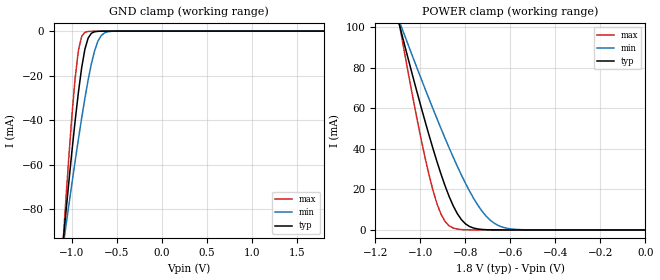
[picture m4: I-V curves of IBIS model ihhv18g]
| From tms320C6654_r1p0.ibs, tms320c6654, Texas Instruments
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|   Model Cell ihhv18g
|ihhv18g (15Jun10 rev 1.0)
[Model]   ihhv18g
Model_type   Input
Polarity   Non-Inverting
Vinl =  0.63
Vinh =  1.17
C_comp   0.720p   0.675p   0.780p
[Model Spec]
Vinl   0.63   0.567   0.693
Vinh   1.17   1.053   1.287
[Temperature Range]   25   125   -40
[Voltage Range]   1.8   1.62   1.98
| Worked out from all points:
|   GND clamp passes 1 mA (typ) near -0.78 V on its own axis
|   POWER clamp passes 1 mA (typ) near -0.77 V on its own axis
[POWER_clamp]
|   voltage   I(typ)   I(min)   I(max)
-1.8V     427.4mA    323.1mA    578.5mA
-1.091V   99.96mA    102mA      99.75mA
-1.073V   92.13mA    96.64mA    88.56mA
-1V       61.75mA    75.45mA    46.3mA
-945.5mV  40.53mA    60.06mA    19.94mA
-909.1mV  27.67mA    50.12mA    7.835mA
-890.9mV  21.84mA    45.28mA    4.198mA
-854.5mV  11.92mA    35.94mA    955.8uA
-800mV    3.016mA    23.04mA    99.12uA
-727.3mV  255.8uA    9.408mA    23.91uA
-636.4mV  15.65uA    1.427mA    11.93uA
0V        9.084nA    6.352nA    18.51nA
[GND_clamp]
|   voltage   I(typ)   I(min)   I(max)
-1.8V     -418.5mA   -315.4mA   -568mA
-1.109V   -99.79mA   -100.3mA   -101.8mA
-1.073V   -84.23mA   -89.57mA   -79.54mA
-1V       -54.36mA   -68.62mA   -38.49mA
-963.6mV  -40.44mA   -58.46mA   -21.38mA
-927.3mV  -27.62mA   -48.59mA   -8.794mA
-854.5mV  -8.093mA   -30.11mA   -555.2uA
-818.2mV  -3.065mA   -21.83mA   -158.2uA
-745.5mV  -287.2uA   -8.633mA   -61.8uA
-672.7mV  -47.68uA   -1.975mA   -44.61uA
-600mV    -23.52uA   -304.6uA   -31.26uA
1.8V      9.084nA    10.54nA    18.45nA
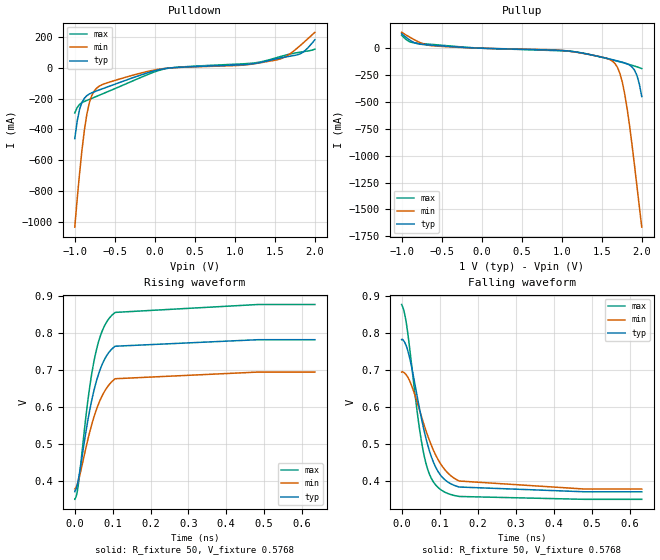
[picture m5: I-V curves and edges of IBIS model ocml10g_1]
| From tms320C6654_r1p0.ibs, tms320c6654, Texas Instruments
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|   Model Cell OCML10G_1
|OCML10G_1
[Model]   ocml10g_1
Model_type   Output
Polarity   Non-Inverting
Cref =  1PF
Rref =  1M
Vref =  0V
Vmeas =  0.5768V
C_comp   1p   1p   1p
| Input capacitance of this buffer has no significance since this is output only
| buffer
[Temperature Range]   25   125   -40
[Voltage Range]   1   0.9   1.1
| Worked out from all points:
|   slope of the pulldown table from 0 to 0.15 V, typ, clamps not added: 9.66 ohm
|   slope of the pullup table from 0 to 0.15 V, typ, clamps not added: 47.7 ohm
|   rising waveform, R_fixture 50, V_fixture 0.5768: 20-80 % time 49.1ps typ, 53.7ps min, 44.6ps max; typ from 0.372 V to 0.781 V
|   falling waveform, R_fixture 50, V_fixture 0.5768: 20-80 % time 54.8ps typ, 70.4ps min, 42.4ps max; typ from 0.782 V to 0.371 V
[Pulldown]
|   voltage   I(typ)   I(min)   I(max)
-1V       -459.5mA   -1.033A    -293.1mA
-969.7mV  -345.3mA   -849.8mA   -257.9mA
-939.4mV  -268.5mA   -680.3mA   -237.8mA
-878.8mV  -197mA     -400.4mA   -218.5mA
-848.5mV  -181mA     -299.6mA   -211.9mA
-787.9mV  -162.9mA   -180.5mA   -198.9mA
-727.3mV  -150.6mA   -132.7mA   -185.8mA
121.2mV   -6.284mA   -5.231mA   -8.248mA
1.212V    24.19mA    22.83mA    28.91mA
1.545V    60.65mA    53.28mA    68.55mA
1.818V    90.11mA    143.8mA    100.5mA
2V        180.8mA    228.9mA    120.2mA
[Pullup]
|   voltage   I(typ)   I(min)   I(max)
-1V       135.5mA    148.5mA    121.9mA
-878.8mV  67.11mA    94.67mA    55.54mA
-636.4mV  29.12mA    25.15mA    37.1mA
1V        -20.19mA   -20.07mA   -23.6mA
1.636V    -106.8mA   -121.2mA   -108.9mA
1.697V    -118.1mA   -178.5mA   -120.6mA
1.727V    -123.9mA   -234.2mA   -126.5mA
1.788V    -136.8mA   -428.2mA   -138.8mA
1.848V    -156.7mA   -724.4mA   -151.7mA
1.909V    -202.8mA   -1.087A    -165.3mA
1.97V     -331.7mA   -1.472A    -180.1mA
2V        -449.3mA   -1.665A    -188.9mA
[Ramp]
| variable   typ   min   max
dV/dt_f   0.248106/55.026052p   0.190656/70.675323p   0.317478/42.516298p
dV/dt_r   0.246402/49.335231p   0.19083/54.65788p   0.315288/44.687748p
R_load = 50
[Rising Waveform]
R_fixture = 50
V_fixture = 0.5768
V_fixture_min = 0.5368
V_fixture_max = 0.6138
|   time   V(typ)   V(min)   V(max)
0s        371.9mV    379.2mV    351.2mV
4.681ps   382.7mV    386.4mV    362.9mV
8.681ps   400.2mV    398.4mV    385.5mV
34.68ps   564.8mV    512.9mV    618.4mV
42.68ps   608mV      545mV      676.2mV
52.68ps   652.9mV    579.7mV    733.4mV
62.68ps   688.4mV    608.1mV    775.7mV
74.68ps   720.2mV    634.9mV    810.5mV
104.7ps   762.4mV    674.7mV    853.5mV
634.1ps   781.5mV    694.3mV    876.4mV
[Falling Waveform]
R_fixture = 50
V_fixture = 0.5768
V_fixture_min = 0.5368
V_fixture_max = 0.6138
0s        781.7mV    694.4mV    876.7mV
9.264ps   771.9mV    690.1mV    844.3mV
19.26ps   740mV      674.3mV    773.8mV
41.26ps   626.1mV    610.7mV    582.9mV
57.26ps   544.1mV    557mV      477.7mV
75.26ps   474.2mV    503.7mV    413.2mV
99.26ps   420.1mV    451.7mV    379.6mV
123.3ps   396.2mV    419.9mV    365.8mV
151.3ps   384mV      400.2mV    358.5mV
630.7ps   371.1mV    378.6mV    350.8mV
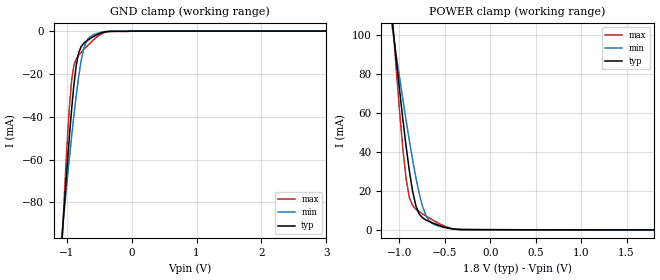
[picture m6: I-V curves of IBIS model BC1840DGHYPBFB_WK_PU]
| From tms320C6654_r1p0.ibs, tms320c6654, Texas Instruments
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|   Model Cell BC1840DGHYPBFB_WK_PU
|BC1840DGHYPBFB_WK_PU
[Model]   BC1840DGHYPBFB_WK_PU
Model_type   Input
Polarity   Non-Inverting
Vinl =  0.63
Vinh =  1.17
C_comp   1.10911p   1.03952p   1.18892p
[Model Spec]
Vinl   0.63   0.5985   0.6615
Vinh   1.17   1.1115   1.2285
D_overshoot_high 2.34 2.34 2.34
D_overshoot_low -0.3 -0.3 -0.3
D_overshoot_time 1.00E-09 1.00E-09 1.00E-09
S_overshoot_high 1.98 1.98 1.98
S_overshoot_low 0 0 0
[Temperature Range]   25   105   -40
[Voltage Range]   1.8   1.71   1.89
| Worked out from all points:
|   GND clamp passes 1 mA (typ) near -0.48 V on its own axis
|   POWER clamp passes 1 mA (typ) near -0.48 V on its own axis
[POWER_clamp]
|   voltage   I(typ)   I(min)   I(max)
-1.8V     457.5mA    350.7mA    618.6mA
-1.073V   104mA      101.6mA    105.6mA
-963.6mV  57.12mA    67.15mA    42mA
-927.3mV  42.94mA    56.22mA    26.36mA
-890.9mV  30.15mA    45.7mA     16.54mA
-854.5mV  19.56mA    35.74mA    12.31mA
-818.2mV  12.08mA    26.56mA    10.46mA
-745.5mV  6.059mA    11.95mA    8.106mA
-709.1mV  4.989mA    7.331mA    7.036mA
-600mV    2.84mA     2.301mA    4.047mA
-345.5mV  117.4uA    127.3uA    127.6uA
1.8V      -99.58uA   -64.22uA   -149.9uA
[GND_clamp]
|   voltage   I(typ)   I(min)   I(max)
-1.8V     -448.8mA   -342.6mA   -610mA
-1.073V   -96.83mA   -94.35mA   -98.27mA
-1.036V   -80.83mA   -82.8mA    -75.88mA
-963.6mV  -50.64mA   -60.42mA   -36.89mA
-927.3mV  -37.05mA   -49.74mA   -23.34mA
-890.9mV  -25.19mA   -39.54mA   -15.97mA
-818.2mV  -10.27mA   -21.49mA   -11.34mA
-745.5mV  -5.941mA   -8.933mA   -8.832mA
-672.7mV  -4.189mA   -3.602mA   -6.523mA
-600mV    -2.783mA   -1.908mA   -4.398mA
-309.1mV  -119.3uA   -82.54uA   -180.5uA
3.6V      0A         0A         0A
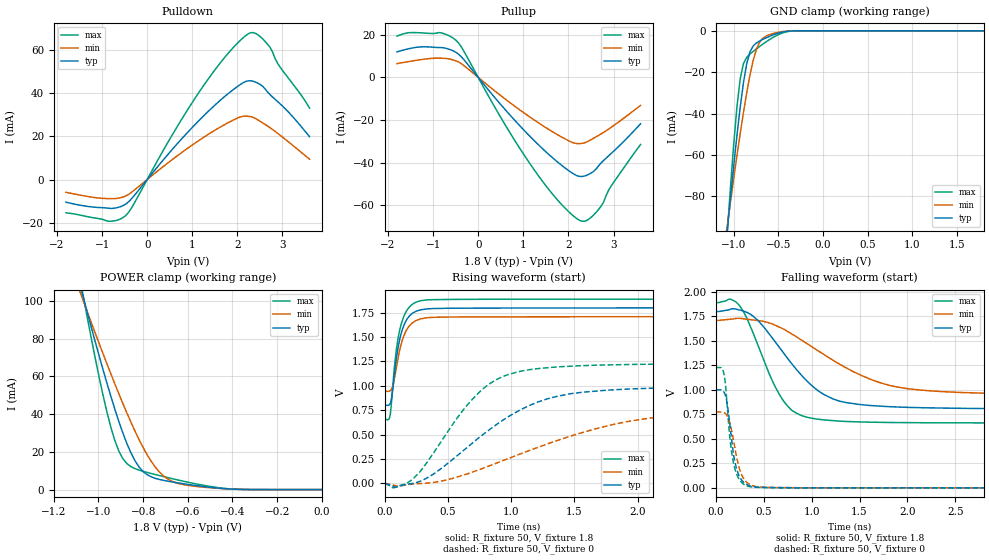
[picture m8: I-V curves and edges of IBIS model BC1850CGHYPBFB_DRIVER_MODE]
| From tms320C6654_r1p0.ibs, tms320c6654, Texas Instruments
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|   Model Cell BC1850CGHYPBFB_DRIVER_MODE
|BC1850CGHYPBFB_DRIVER_MODE
[Model]   BC1850CGHYPBFB_DRIVER_MODE
Model_type   I/O
Polarity   Non-Inverting
Enable   Active-Low
Vinl =  0.63
Vinh =  1.17
Cref = 5.0000pF
Rref =  100.0000M
Vref =  0V
Vmeas =  0.9
C_comp   1.03817p   0.972267p   1.11381p
[Model Spec]
Vinl   0.63   0.5985   0.6615
Vinh   1.17   1.1115   1.2285
D_overshoot_high 2.34 2.34 2.34
D_overshoot_low -0.3 -0.3 -0.3
D_overshoot_time 1.00E-09 1.00E-09 1.00E-09
S_overshoot_high 1.98 1.98 1.98
S_overshoot_low 0 0 0
[Temperature Range]   25   105   -40
[Voltage Range]   1.8   1.71   1.89
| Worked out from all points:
|   slope of the pulldown table from 0 to 0.27 V, typ, clamps not added: 38.9 ohm
|   slope of the pullup table from 0 to 0.27 V, typ, clamps not added: 38.5 ohm
|   GND clamp passes 1 mA (typ) near -0.49 V on its own axis
|   POWER clamp passes 1 mA (typ) near -0.48 V on its own axis
|   rising waveform, R_fixture 50, V_fixture 1.8: 20-80 % time 78.8ps typ, 86.2ps min, 74.9ps max; typ from 0.807 V to 1.8 V
|   rising waveform, R_fixture 50, V_fixture 0: 20-80 % time 652ps typ, 1.09ns min, 440ps max; typ from 0 V to 0.999 V
|   falling waveform, R_fixture 50, V_fixture 1.8: 20-80 % time 517ps typ, 822ps min, 331ps max; typ from 1.8 V to 0.806 V
|   falling waveform, R_fixture 50, V_fixture 0: 20-80 % time 87.6ps typ, 103ps min, 78.9ps max; typ from 1 V to 0 V
[POWER_clamp]
|   voltage   I(typ)   I(min)   I(max)
-1.8V     457.5mA    350.7mA    618.6mA
-1.073V   104mA      101.5mA    105.5mA
-1.055V   95.87mA    95.68mA    93.98mA
-1V       72.13mA    78.37mA    61.22mA
-945.5mV  49.82mA    61.61mA    33.45mA
-909.1mV  36.25mA    50.87mA    20.48mA
-872.7mV  24.44mA    40.61mA    13.8mA
-800mV    9.556mA    22.31mA    9.682mA
-727.3mV  5.377mA    9.342mA    7.443mA
-654.5mV  3.753mA    3.696mA    5.378mA
-400mV    266.8uA    273.8uA    300.1uA
0V        10.43nA    15.61nA    15.97nA
[Pulldown]
|   voltage   I(typ)   I(min)   I(max)
-1.8V     -10.49mA   -5.94mA    -15.44mA
-872.7mV  -13.28mA   -8.846mA   -19.37mA
-490.9mV  -11.6mA    -7.765mA   -16.98mA
-327.3mV  -8.437mA   -5.603mA   -12.48mA
490.9mV   12.41mA    8.221mA    18.41mA
1.2V      28.49mA    18.87mA    42.06mA
1.855V    40.86mA    27.04mA    60mA
2.291V    45.84mA    29.18mA    68.13mA
2.455V    44.73mA    27.66mA    67.19mA
2.673V    40.54mA    24.78mA    62.7mA
2.891V    36.19mA    21.48mA    53.96mA
3.6V      19.87mA    9.45mA     33.15mA
[Pullup]
|   voltage   I(typ)   I(min)   I(max)
-1.8V     11.99mA    6.48mA     19.36mA
-1.309V   14.25mA    8.213mA    20.96mA
-872.7mV  13.99mA    9.018mA    21.04mA
-490.9mV  11.72mA    7.718mA    17.37mA
600mV     -15.19mA   -10.2mA    -22.37mA
1.145V    -27.66mA   -18.63mA   -40.48mA
1.745V    -39.51mA   -26.77mA   -57.27mA
2.236V    -46.48mA   -31.14mA   -67.04mA
2.4V      -46.04mA   -30.43mA   -67.27mA
2.673V    -41.48mA   -27.21mA   -61.93mA
2.945V    -35.82mA   -23.52mA   -51.11mA
3.6V      -21.79mA   -13.16mA   -31.53mA
[GND_clamp]
|   voltage   I(typ)   I(min)   I(max)
-1.8V     -448.8mA   -342.6mA   -610mA
-1.073V   -96.78mA   -94.34mA   -98.17mA
-1.036V   -80.78mA   -82.78mA   -75.78mA
-963.6mV  -50.58mA   -60.4mA    -36.78mA
-927.3mV  -36.98mA   -49.71mA   -23.23mA
-890.9mV  -25.12mA   -39.52mA   -15.86mA
-854.5mV  -15.96mA   -30.01mA   -12.84mA
-818.2mV  -10.19mA   -21.46mA   -11.22mA
-745.5mV  -5.863mA   -8.89mA    -8.713mA
-636.4mV  -3.378mA   -2.511mA   -5.306mA
-345.5mV  -56.35uA   -45.43uA   -97.06uA
1.8V      10.43nA    77.52nA    15.84nA
[Ramp]
| variable   typ   min   max
dV/dt_f   0.614472/0.52822932n   0.47157/0.83950154n   0.758814/0.33831193n
dV/dt_r  0.6235026/0.66882898n  0.4837782/1.1184342n   0.766041/0.45055837n
R_load = 50
[Rising Waveform]
R_fixture = 50
V_fixture = 1.8
V_fixture_min = 1.71
V_fixture_max = 1.89
|   time   V(typ)   V(min)   V(max)
0s        806.9mV    947mV      662.1mV
41.85ps   815.1mV    949.1mV    694.7mV
55.46ps   887.2mV    970.4mV    878.2mV
73.64ps   1.092V     1.057V     1.163V
90.83ps   1.275V     1.186V     1.366V
109.4ps   1.424V     1.319V     1.52V
134ps     1.559V     1.451V     1.652V
191.3ps   1.712V     1.611V     1.804V
289.3ps   1.781V     1.689V     1.875V
4.965ns   1.8V       1.71V      1.89V
[Rising Waveform]
R_fixture = 50
V_fixture = 0
V_fixture_min = 0
V_fixture_max = 0
|   time   V(typ)   V(min)   V(max)
0s        0V         0V         0V
71.55ps   -35.14mV   -20.62mV   -46.99mV
207.6ps   -5.47mV    -9.875mV   28.97mV
388.1ps   96.57mV    8.689mV    316mV
759.8ps   482.6mV    145.3mV    949.5mV
919.3ps   634.8mV    224.2mV    1.087V
1.107ns   775.5mV    317.8mV    1.158V
1.464ns   917.9mV    481.4mV    1.201V
2.348ns   982.8mV    704.6mV    1.225V
4.965ns   999.4mV    775mV      1.229V
[Falling Waveform]
R_fixture = 50
V_fixture = 1.8
V_fixture_min = 1.71
V_fixture_max = 1.89
|   time   V(typ)   V(min)   V(max)
0s        1.8V       1.709V     1.89V
145.3ps   1.82V      1.72V      1.927V
242.5ps   1.817V     1.732V     1.867V
439.3ps   1.71V      1.71V      1.455V
664.7ps   1.432V     1.641V     950.6mV
797.2ps   1.262V     1.57V      789.1mV
953.5ps   1.089V     1.471V     720.7mV
1.291ns   885.1mV    1.263V     681.1mV
1.999ns   821.8mV    1.013V     665.6mV
4.965ns   805.9mV    946.6mV    662.5mV
[Falling Waveform]
R_fixture = 50
V_fixture = 0
V_fixture_min = 0
V_fixture_max = 0
|   time   V(typ)   V(min)   V(max)
0s        999.8mV    775.2mV    1.228V
57.9ps    999.4mV    775.8mV    1.226V
87.43ps   973.4mV    768.3mV    1.153V
118.6ps   862.1mV    735.5mV    840.1mV
151.1ps   602.8mV    646.4mV    470.1mV
196.9ps   277.6mV    416.4mV    201.2mV
258.9ps   94.56mV    158.2mV    66.95mV
334.4ps   28.2mV     48.13mV    16.1mV
592.9ps   3.231mV    3.261mV    2.282mV
4.965ns   0V         0V         0V
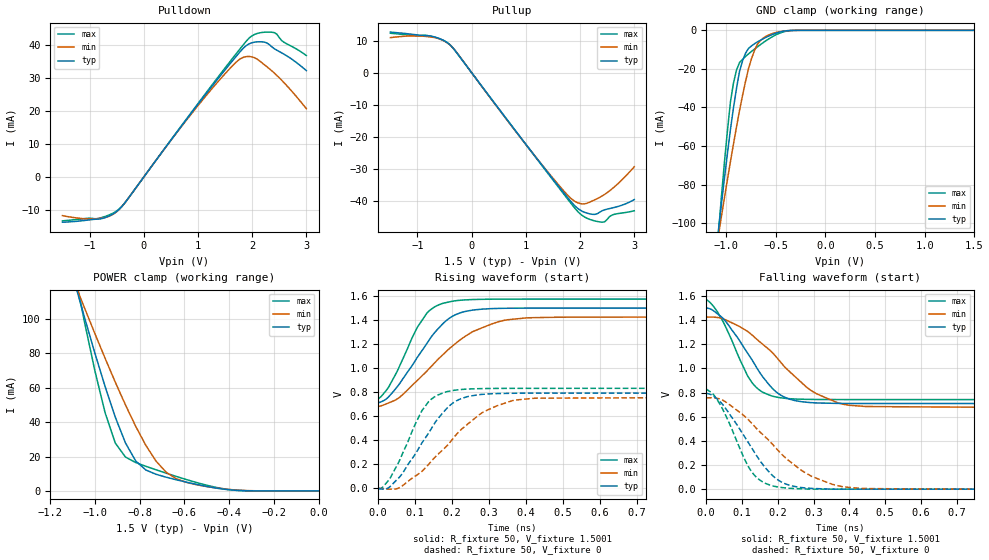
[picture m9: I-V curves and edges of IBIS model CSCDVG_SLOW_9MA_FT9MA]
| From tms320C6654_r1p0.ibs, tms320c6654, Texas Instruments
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|   Model Cell CSCDVG_SLOW_9MA_FT9MA
|SLOW_9MA
[Model]   CSCDVG_SLOW_9MA_FT9MA
Model_type   I/O
Polarity   Non-Inverting
Enable   Active-Low
Cref =  4.0000pF
Rref =  100.0000M
Vref =  0V
Vmeas =  0.75
C_comp   1.5249p   1.4275p   1.6205p
|[mode_tieoffpin] SR1=1  SR0=0 I0=1 I1=0 I2=1
[Model Spec]
Vinl   0.6125   0.6125   0.6125
Vinh   0.9625   0.9625   0.9625
D_overshoot_high 1.95 1.95 1.95
D_overshoot_low -0.3 -0.3 -0.3
D_overshoot_time 1E-9 1E-9 1E-9
S_overshoot_high 1.575 1.575 1.575
S_overshoot_low 0 0 0
[Receiver Thresholds]
Reference_supply Pullup_ref
Threshold_sensitivity= 0.5
Tslew_ac= 5nS
Vinh_ac= +175mV
Vinh_dc= +100mV
Vinl_ac= -175mV
Vinl_dc= -100mV
Vth = 0.75
Vth_max= 0.79
Vth_min= 0.71
[Pullup Reference] 1.5001   1.425   1.575
[Add Submodel]
|Submodel_name Mode
CSCDVG_FT_TH_9MA Non-Driving
[Temperature Range]   25   105   -40
[Voltage Range]   1.5   1.425   1.575
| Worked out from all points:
|   slope of the pulldown table from 0 to 0.225 V, typ, clamps not added: 44.4 ohm
|   slope of the pullup table from 0 to 0.225 V, typ, clamps not added: 44.4 ohm
|   GND clamp passes 1 mA (typ) near -0.47 V on its own axis
|   POWER clamp passes 1 mA (typ) near -0.42 V on its own axis
|   rising waveform, R_fixture 50, V_fixture 1.5001: 20-80 % time 109ps typ, 159ps min, 80.9ps max; typ from 0.71 V to 1.5 V
|   rising waveform, R_fixture 50, V_fixture 0: 20-80 % time 104ps typ, 149ps min, 76.5ps max; typ from 0 V to 0.793 V
|   falling waveform, R_fixture 50, V_fixture 1.5001: 20-80 % time 109ps typ, 160ps min, 79ps max; typ from 1.5 V to 0.709 V
|   falling waveform, R_fixture 50, V_fixture 0: 20-80 % time 108ps typ, 161ps min, 76.4ps max; typ from 0.792 V to 0 V
[POWER_clamp]
|   voltage   I(typ)   I(min)   I(max)
-1.5V     321.7mA    260.6mA    415.9mA
-1.076V   114.2mA    115.8mA    116.9mA
-1.061V   107.2mA    110.9mA    107.1mA
-954.6mV  60.59mA    77.06mA    45.35mA
-909.2mV  42.85mA    63.21mA    27.81mA
-863.7mV  27.9mA     49.99mA    19.69mA
-818.2mV  17.49mA    37.63mA    16.52mA
-772.8mV  12.19mA    26.53mA    14.33mA
-681.9mV  7.985mA    10.89mA    10.33mA
-590.9mV  5.094mA    4.955mA    6.6mA
-363.7mV  298.5uA    465.2uA    297.6uA
0V        1.518nA    24.08nA    367.8pA
[Pulldown]
|   voltage   I(typ)   I(min)   I(max)
-1.5V     -13.72mA   -11.73mA   -13.31mA
-863.7mV  -12.8mA    -12.65mA   -12.66mA
-500mV    -10.46mA   -10.55mA   -10.29mA
-318.2mV  -7.172mA   -7.186mA   -7.182mA
1.046V    23.05mA    22.61mA    23.31mA
1.591V    34.39mA    33mA       35.06mA
1.818V    38.82mA    36.24mA    39.81mA
1.955V    40.55mA    36.61mA    42.37mA
2.091V    41.08mA    35.83mA    43.61mA
2.273V    40.74mA    33.5mA     44.04mA
2.364V    39.55mA    32.26mA    43.99mA
3V        32.34mA    20.77mA    36.92mA
[Pullup]
|   voltage   I(typ)   I(min)   I(max)
-1.5V     12.66mA    10.94mA    12.31mA
-818.2mV  11.55mA    11.26mA    11.58mA
-590.9mV  10.61mA    10.52mA    10.54mA
-409.1mV  8.836mA    8.777mA    8.84mA
1.227V    -27.25mA   -27.19mA   -27.38mA
1.727V    -37.96mA   -37.32mA   -38.38mA
1.909V    -41.55mA   -40.1mA    -42.29mA
2.046V    -43.18mA   -40.84mA   -44.51mA
2.227V    -44.08mA   -39.9mA    -45.94mA
2.409V    -42.96mA   -38.35mA   -46.53mA
2.591V    -42.11mA   -36.14mA   -44.31mA
3V        -39.5mA    -29.28mA   -42.98mA
[GND_clamp]
|   voltage   I(typ)   I(min)   I(max)
-1.5V     -310.1mA   -250.5mA   -402.5mA
-1.076V   -103.6mA   -106.2mA   -105.2mA
-1.046V   -89.81mA   -96.36mA   -86.02mA
-954.6mV  -51.22mA   -67.87mA   -36.88mA
-924.3mV  -40.08mA   -58.86mA   -27.29mA
-863.7mV  -21.24mA   -41.56mA   -16.73mA
-833.4mV  -15.8mA    -33.75mA   -15.03mA
-772.8mV  -9.345mA   -19.75mA   -12.19mA
-712.2mV  -6.928mA   -10.35mA   -9.704mA
-621.3mV  -4.261mA   -3.896mA   -6.225mA
-409.1mV  -337.1uA   -289.1uA   -618.9uA
1.5V      1.518nA    257.2nA    299pA
[Ramp]
| variable   typ   min   max
dV/dt_f   0.632752/0.15851914n   0.5992/0.24547647n   0.666584/0.12022051n
dV/dt_r  0.6390308/0.15258712n 0.61063504/0.23050864n 0.66840112/0.11552235n
R_load = 50
[Rising Waveform]
R_fixture = 50
V_fixture = 1.5001
V_fixture_min = 1.425
V_fixture_max = 1.575
|   time   V(typ)   V(min)   V(max)
0s        709.9mV    677.9mV    742.7mV
24.12ps   750mV      706.1mV    824.4mV
47.16ps   828.8mV    736.4mV    949.3mV
105.8ps   1.089V     897mV      1.339V
132.1ps   1.206V     977.1mV    1.459V
198.6ps   1.427V     1.178V     1.556V
252.4ps   1.482V     1.298V     1.571V
307.2ps   1.496V     1.368V     1.574V
403.4ps   1.5V       1.419V     1.575V
1.289ns   1.5V       1.425V     1.575V
[Rising Waveform]
R_fixture = 50
V_fixture = 0
V_fixture_min = 0
V_fixture_max = 0
|   time   V(typ)   V(min)   V(max)
0s        0V         0V         0V
33.56ps   19.21mV    -5.825mV   91.71mV
64.18ps   118.9mV    19.13mV    277.9mV
119.6ps   383.8mV    145mV      652.4mV
146.6ps   511.1mV    235.5mV    748.6mV
189.1ps   676mV      364.5mV    807mV
226.7ps   749.4mV    495.2mV    823.4mV
279.7ps   781.9mV    625.7mV    830.3mV
374.5ps   791.8mV    736.1mV    832.4mV
1.296ns   793mV      756.2mV    832.8mV
[Falling Waveform]
R_fixture = 50
V_fixture = 1.5001
V_fixture_min = 1.425
V_fixture_max = 1.575
|   time   V(typ)   V(min)   V(max)
0s        1.499V     1.425V     1.575V
20.88ps   1.477V     1.425V     1.514V
51.85ps   1.4V       1.406V     1.361V
127.6ps   1.073V     1.278V     884.7mV
155.2ps   942.6mV    1.207V     808mV
194.6ps   807.9mV    1.099V     763.9mV
231.9ps   746.6mV    976.8mV    749.5mV
291.8ps   716.9mV    819.5mV    743.5mV
399.6ps   709.8mV    695mV      742.1mV
1.289ns   709.3mV    676.9mV    741.9mV
[Falling Waveform]
R_fixture = 50
V_fixture = 0
V_fixture_min = 0
V_fixture_max = 0
|   time   V(typ)   V(min)   V(max)
0s        792.2mV    755.8mV    831.9mV
41.25ps   717.6mV    743.5mV    690.4mV
105.4ps   443.3mV    609.5mV    260.4mV
127.6ps   340.1mV    544.4mV    142.4mV
150.8ps   233.7mV    472.4mV    73.44mV
188.3ps   105.1mV    362.5mV    25.09mV
221.6ps   43.61mV    259.5mV    10.2mV
269.9ps   12.26mV    148.6mV    2.832mV
383.4ps   0V         19.15mV    0V
1.296ns   0V         0V         0V
